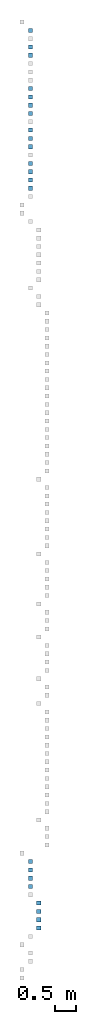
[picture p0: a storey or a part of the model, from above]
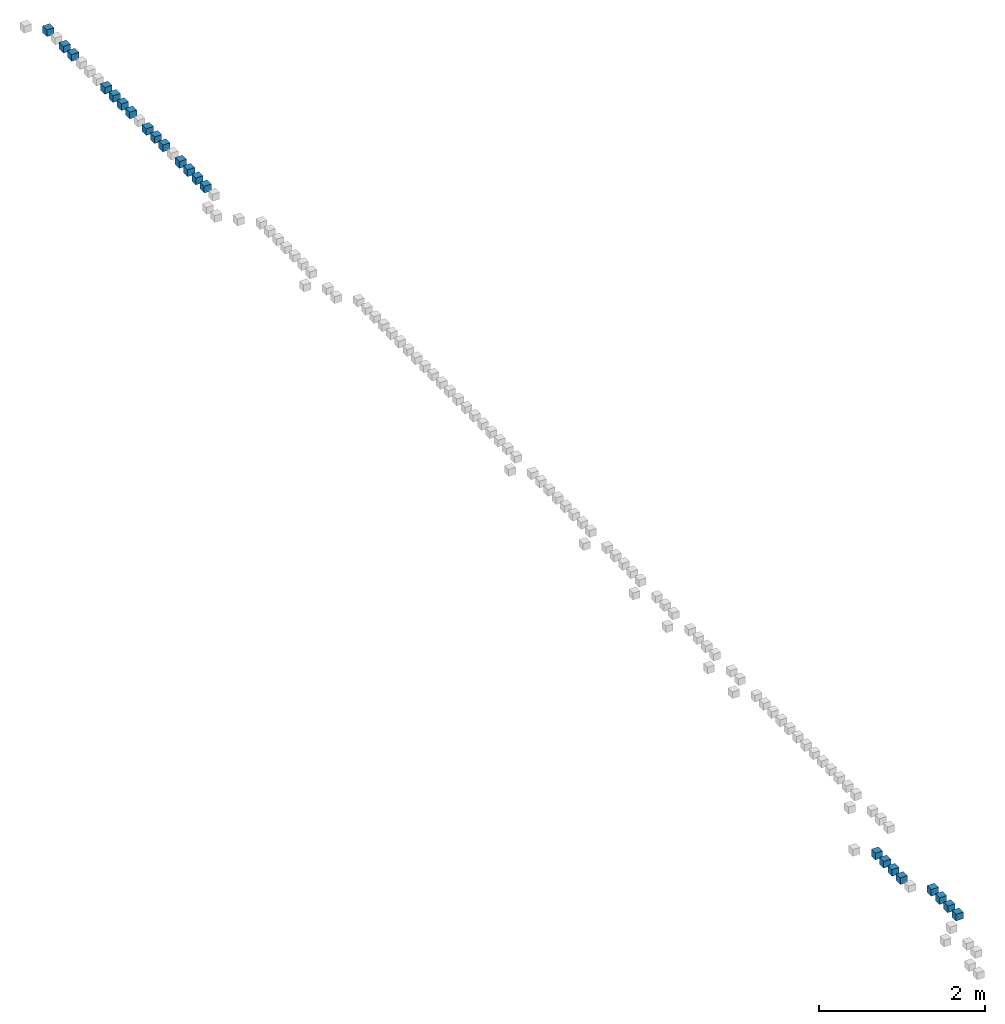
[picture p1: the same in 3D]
Properties of the parts of a building model (IFC4)

# File
Description: ViewDefinition [DesignTransferView_V1.0]
File name: 0001
Time: 2021-10-22T16:53:55
Written by: The EXPRESS Data Manager Version 5.02.0100.07 : 28 Aug 2013
Made in: 22.0.2.392 - Exporter 22.0.2.392 - Alternate UI 22.0.2.392

# IfcProject, 0001
LongName: Project Name; Phase: Project Status

# IfcSite, Default
RefLatitude: 42, 21, 31, 181945; RefLongitude: -71, -3, -24, -263305; RefElevation: 0 mm

# IfcSite: Generic Ifc Family:Generic Ifc Family, Generic Ifc Family:Generic Ifc Family:350329
Material: <Unnamed>

# IfcBuildingStorey: Level:8mm Head, Level 1
LongName: Level 1; Elevation: 0 mm

# IfcSpace: Generic Ifc Family:Generic Ifc Family, Generic Ifc Family:Generic Ifc Family:350332
Type - Material: <Unnamed>

# IfcActuator: Generic Ifc Family:Generic Ifc Family, Generic Ifc Family:Generic Ifc Family:349744
In: Level 1
Type - Material: <Unnamed>

# IfcAirTerminal: Generic Ifc Family:Generic Ifc Family, Generic Ifc Family:Generic Ifc Family:350142
In: Level 1
Type - Material: <Unnamed>

# IfcAirTerminalBox: Generic Ifc Family:Generic Ifc Family, Generic Ifc Family:Generic Ifc Family:349960
In: Level 1
Type - Material: <Unnamed>

# IfcAirToAirHeatRecovery: Generic Ifc Family:Generic Ifc Family, Generic Ifc Family:Generic Ifc Family:349855
In: Level 1
Type - Material: <Unnamed>

# IfcAlarm: Generic Ifc Family:Generic Ifc Family, Generic Ifc Family:Generic Ifc Family:349777
In: Level 1
Type - Material: <Unnamed>

# IfcAudioVisualAppliance: Generic Ifc Family:Generic Ifc Family, Generic Ifc Family:Generic Ifc Family:350154
In: Level 1
Type - Material: <Unnamed>

# IfcBeam: Generic Ifc Family:Generic Ifc Family, Generic Ifc Family:Generic Ifc Family:349537
In: Level 1
Type - PredefinedType: BEAM; Material: <Unnamed>

# IfcBoiler: Generic Ifc Family:Generic Ifc Family, Generic Ifc Family:Generic Ifc Family:349875
In: Level 1
Type - Material: <Unnamed>

# IfcBuildingElementPart: Generic Ifc Family:Generic Ifc Family, Generic Ifc Family:Generic Ifc Family:350225
In: Level 1
Type - Material: <Unnamed>

# IfcBuildingElementProxy: Generic Ifc Family:Generic Ifc Family (4)
In: Level 1
Type - Material: <Unnamed>
Name (Generic Ifc Family:Generic Ifc Family:...)
349545
349619
350213
350262

# IfcBurner: Generic Ifc Family:Generic Ifc Family, Generic Ifc Family:Generic Ifc Family:349888
In: Level 1
Type - Material: <Unnamed>

# IfcCableCarrierFitting: Generic Ifc Family:Generic Ifc Family, Generic Ifc Family:Generic Ifc Family:350023
In: Level 1
Type - Material: <Unnamed>

# IfcCableCarrierSegment: Generic Ifc Family:Generic Ifc Family, Generic Ifc Family:Generic Ifc Family:350096
In: Level 1
Type - Material: <Unnamed>

# IfcCableFitting: Generic Ifc Family:Generic Ifc Family, Generic Ifc Family:Generic Ifc Family:350039
In: Level 1
Type - Material: <Unnamed>

# IfcCableSegment: Generic Ifc Family:Generic Ifc Family, Generic Ifc Family:Generic Ifc Family:350097
In: Level 1
Type - Material: <Unnamed>

# IfcChiller: Generic Ifc Family:Generic Ifc Family, Generic Ifc Family:Generic Ifc Family:349891
In: Level 1
Type - Material: <Unnamed>

# IfcChimney: Generic Ifc Family:Generic Ifc Family, Generic Ifc Family:Generic Ifc Family:349558
In: Level 1
Type - Material: <Unnamed>

# IfcCivilElement: Generic Ifc Family:Generic Ifc Family, Generic Ifc Family:Generic Ifc Family:349694
In: Level 1
Type - Material: <Unnamed>

# IfcCoil: Generic Ifc Family:Generic Ifc Family, Generic Ifc Family:Generic Ifc Family:349894
In: Level 1
Type - Material: <Unnamed>

# IfcColumn: Generic Ifc Family:Generic Ifc Family, Generic Ifc Family:Generic Ifc Family:349561
In: Level 1
Type - PredefinedType: COLUMN; Material: <Unnamed>

# IfcCommunicationsAppliance: Generic Ifc Family:Generic Ifc Family, Generic Ifc Family:Generic Ifc Family:350167
In: Level 1
Type - Material: <Unnamed>

# IfcCompressor: Generic Ifc Family:Generic Ifc Family, Generic Ifc Family:Generic Ifc Family:350077
In: Level 1
Type - Material: <Unnamed>

# IfcCondenser: Generic Ifc Family:Generic Ifc Family, Generic Ifc Family:Generic Ifc Family:349897
In: Level 1
Type - Material: <Unnamed>

# IfcController: Generic Ifc Family:Generic Ifc Family, Generic Ifc Family:Generic Ifc Family:349790
In: Level 1
Type - Material: <Unnamed>

# IfcCooledBeam: Generic Ifc Family:Generic Ifc Family, Generic Ifc Family:Generic Ifc Family:349900
In: Level 1
Type - Material: <Unnamed>

# IfcCoolingTower: Generic Ifc Family:Generic Ifc Family, Generic Ifc Family:Generic Ifc Family:349903
In: Level 1
Type - Material: <Unnamed>

# IfcCurtainWall: Generic Ifc Family:Generic Ifc Family, Generic Ifc Family:Generic Ifc Family:349567
In: Level 1
Type - Material: <Unnamed>

# IfcDamper: Generic Ifc Family:Generic Ifc Family, Generic Ifc Family:Generic Ifc Family:349978
In: Level 1
Type - Material: <Unnamed>

# IfcDiscreteAccessory: Generic Ifc Family:Generic Ifc Family, Generic Ifc Family:Generic Ifc Family:350243
In: Level 1
Type - Material: <Unnamed>

# IfcDistributionChamberElement: Generic Ifc Family:Generic Ifc Family, Generic Ifc Family:Generic Ifc Family:349829
In: Level 1
Type - Material: <Unnamed>

# IfcDistributionControlElement: Generic Ifc Family:Generic Ifc Family, Generic Ifc Family:Generic Ifc Family:349720
In: Level 1
Type - Material: <Unnamed>

# IfcDistributionElement: Generic Ifc Family:Generic Ifc Family, Generic Ifc Family:Generic Ifc Family:349710
In: Level 1
Type - Material: <Unnamed>

# IfcDistributionFlowElement: Generic Ifc Family:Generic Ifc Family, Generic Ifc Family:Generic Ifc Family:349813
In: Level 1
Type - Material: <Unnamed>

# IfcDoor: Generic Ifc Family:Generic Ifc Family, Generic Ifc Family:Generic Ifc Family:349570
In: Level 1
Type - PredefinedType: DOOR; ParameterTakesPrecedence: no; Material: <Unnamed>
OverallHeight: 100 mm; OverallWidth: 100 mm

# IfcDuctFitting: Generic Ifc Family:Generic Ifc Family, Generic Ifc Family:Generic Ifc Family:350052
In: Level 1
Type - Material: <Unnamed>

# IfcDuctSegment: Generic Ifc Family:Generic Ifc Family, Generic Ifc Family:Generic Ifc Family:350098
In: Level 1
Type - Material: <Unnamed>

# IfcDuctSilencer: Generic Ifc Family:Generic Ifc Family, Generic Ifc Family:Generic Ifc Family:350201
In: Level 1
Type - Material: <Unnamed>

# IfcElectricAppliance: Generic Ifc Family:Generic Ifc Family, Generic Ifc Family:Generic Ifc Family:350170
In: Level 1
Type - Material: <Unnamed>

# IfcElectricDistributionBoard: Generic Ifc Family:Generic Ifc Family, Generic Ifc Family:Generic Ifc Family:349991
In: Level 1
Type - Material: <Unnamed>

# IfcElectricFlowStorageDevice: Generic Ifc Family:Generic Ifc Family, Generic Ifc Family:Generic Ifc Family:350119
In: Level 1
Type - Material: <Unnamed>

# IfcElectricGenerator: Generic Ifc Family:Generic Ifc Family, Generic Ifc Family:Generic Ifc Family:349906
In: Level 1
Type - Material: <Unnamed>

# IfcElectricMotor: Generic Ifc Family:Generic Ifc Family, Generic Ifc Family:Generic Ifc Family:349909
In: Level 1
Type - Material: <Unnamed>

# IfcElectricTimeControl: Generic Ifc Family:Generic Ifc Family, Generic Ifc Family:Generic Ifc Family:349994
In: Level 1
Type - Material: <Unnamed>

# IfcEnergyConversionDevice: Generic Ifc Family:Generic Ifc Family, Generic Ifc Family:Generic Ifc Family:349845
In: Level 1
Type - Material: <Unnamed>

# IfcEngine: Generic Ifc Family:Generic Ifc Family, Generic Ifc Family:Generic Ifc Family:349912
In: Level 1
Type - Material: <Unnamed>

# IfcEvaporativeCooler: Generic Ifc Family:Generic Ifc Family, Generic Ifc Family:Generic Ifc Family:349915
In: Level 1
Type - Material: <Unnamed>

# IfcEvaporator: Generic Ifc Family:Generic Ifc Family, Generic Ifc Family:Generic Ifc Family:349918
In: Level 1
Type - Material: <Unnamed>

# IfcFan: Generic Ifc Family:Generic Ifc Family, Generic Ifc Family:Generic Ifc Family:350078
In: Level 1
Type - Material: <Unnamed>

# IfcFastener: Generic Ifc Family:Generic Ifc Family, Generic Ifc Family:Generic Ifc Family:350256
In: Level 1
Type - Material: <Unnamed>

# IfcFilter: Generic Ifc Family:Generic Ifc Family, Generic Ifc Family:Generic Ifc Family:350202
In: Level 1
Type - Material: <Unnamed>

# IfcFireSuppressionTerminal: Generic Ifc Family:Generic Ifc Family, Generic Ifc Family:Generic Ifc Family:350173
In: Level 1
Type - Material: <Unnamed>

# IfcFlowController: Generic Ifc Family:Generic Ifc Family, Generic Ifc Family:Generic Ifc Family:349942
In: Level 1
Type - Material: <Unnamed>

# IfcFlowFitting: Generic Ifc Family:Generic Ifc Family, Generic Ifc Family:Generic Ifc Family:350009
In: Level 1
Type - Material: <Unnamed>

# IfcFlowInstrument: Generic Ifc Family:Generic Ifc Family, Generic Ifc Family:Generic Ifc Family:349793
In: Level 1
Type - Material: <Unnamed>

# IfcFlowMeter: Generic Ifc Family:Generic Ifc Family, Generic Ifc Family:Generic Ifc Family:349997
In: Level 1
Type - Material: <Unnamed>

# IfcFlowMovingDevice: Generic Ifc Family:Generic Ifc Family, Generic Ifc Family:Generic Ifc Family:350061
In: Level 1
Type - Material: <Unnamed>

# IfcFlowSegment: Generic Ifc Family:Generic Ifc Family, Generic Ifc Family:Generic Ifc Family:350095
In: Level 1
Type - Material: <Unnamed>

# IfcFlowStorageDevice: Generic Ifc Family:Generic Ifc Family, Generic Ifc Family:Generic Ifc Family:350118
In: Level 1
Type - Material: <Unnamed>

# IfcFlowTerminal: Generic Ifc Family:Generic Ifc Family, Generic Ifc Family:Generic Ifc Family:350141
In: Level 1
Type - Material: <Unnamed>

# IfcFlowTreatmentDevice: Generic Ifc Family:Generic Ifc Family, Generic Ifc Family:Generic Ifc Family:350200
In: Level 1
Type - Material: <Unnamed>

# IfcFooting: Generic Ifc Family:Generic Ifc Family, Generic Ifc Family:Generic Ifc Family:349573
In: Level 1
Type - Material: <Unnamed>

# IfcFurnishingElement: Generic Ifc Family:Generic Ifc Family, Generic Ifc Family:Generic Ifc Family:350292
In: Level 1
Type - Material: <Unnamed>

# IfcFurniture: Generic Ifc Family:Generic Ifc Family, Generic Ifc Family:Generic Ifc Family:350293
In: Level 1
Type - Material: <Unnamed>

# IfcGeographicElement: Generic Ifc Family:Generic Ifc Family, Generic Ifc Family:Generic Ifc Family:350304
In: Level 1
Type - Material: <Unnamed>

# IfcHeatExchanger: Generic Ifc Family:Generic Ifc Family, Generic Ifc Family:Generic Ifc Family:349921
In: Level 1
Type - Material: <Unnamed>

# IfcHumidifier: Generic Ifc Family:Generic Ifc Family, Generic Ifc Family:Generic Ifc Family:349924
In: Level 1
Type - Material: <Unnamed>

# IfcInterceptor: Generic Ifc Family:Generic Ifc Family, Generic Ifc Family:Generic Ifc Family:350203
In: Level 1
Type - Material: <Unnamed>

# IfcJunctionBox: Generic Ifc Family:Generic Ifc Family, Generic Ifc Family:Generic Ifc Family:350055
In: Level 1
Type - Material: <Unnamed>

# IfcLamp: Generic Ifc Family:Generic Ifc Family, Generic Ifc Family:Generic Ifc Family:350176
In: Level 1
Type - Material: <Unnamed>

# IfcLightFixture: Generic Ifc Family:Generic Ifc Family, Generic Ifc Family:Generic Ifc Family:350179
In: Level 1
Type - Material: <Unnamed>

# IfcMechanicalFastener: Generic Ifc Family:Generic Ifc Family, Generic Ifc Family:Generic Ifc Family:350259
In: Level 1
Type - Material: <Unnamed>

# IfcMedicalDevice: Generic Ifc Family:Generic Ifc Family, Generic Ifc Family:Generic Ifc Family:350182
In: Level 1
Type - Material: <Unnamed>

# IfcMember: Generic Ifc Family:Generic Ifc Family, Generic Ifc Family:Generic Ifc Family:349576
In: Level 1
Type - PredefinedType: BRACE; Material: <Unnamed>

# IfcMotorConnection: Generic Ifc Family:Generic Ifc Family, Generic Ifc Family:Generic Ifc Family:349927
In: Level 1
Type - Material: <Unnamed>

# IfcOutlet: Generic Ifc Family:Generic Ifc Family, Generic Ifc Family:Generic Ifc Family:350185
In: Level 1
Type - Material: <Unnamed>

# IfcPile: Generic Ifc Family:Generic Ifc Family, Generic Ifc Family:Generic Ifc Family:349579
In: Level 1
Type - Material: <Unnamed>

# IfcPipeFitting: Generic Ifc Family:Generic Ifc Family, Generic Ifc Family:Generic Ifc Family:350058
In: Level 1
Type - Material: <Unnamed>

# IfcPipeSegment: Generic Ifc Family:Generic Ifc Family, Generic Ifc Family:Generic Ifc Family:350108
In: Level 1
Type - Material: <Unnamed>

# IfcPlate: Generic Ifc Family:Generic Ifc Family, Generic Ifc Family:Generic Ifc Family:349582
In: Level 1
Type - Material: <Unnamed>

# IfcProtectiveDevice: Generic Ifc Family:Generic Ifc Family, Generic Ifc Family:Generic Ifc Family:350000
In: Level 1
Type - Material: <Unnamed>

# IfcProtectiveDeviceTrippingUnit: Generic Ifc Family:Generic Ifc Family, Generic Ifc Family:Generic Ifc Family:349796
In: Level 1
Type - Material: <Unnamed>

# IfcPump: Generic Ifc Family:Generic Ifc Family, Generic Ifc Family:Generic Ifc Family:350079
In: Level 1
Type - Material: <Unnamed>

# IfcRailing: Generic Ifc Family:Generic Ifc Family, Generic Ifc Family:Generic Ifc Family:349585
In: Level 1
Type - Material: <Unnamed>

# IfcRamp: Generic Ifc Family:Generic Ifc Family, Generic Ifc Family:Generic Ifc Family:349588
In: Level 1
Material: <Unnamed>

# IfcRampFlight: Generic Ifc Family:Generic Ifc Family, Generic Ifc Family:Generic Ifc Family:349591
In: Level 1
Type - Material: <Unnamed>

# IfcReinforcingBar: Generic Ifc Family:Generic Ifc Family, Generic Ifc Family:Generic Ifc Family:350265
In: Level 1
Type - Material: <Unnamed>

# IfcReinforcingMesh: Generic Ifc Family:Generic Ifc Family, Generic Ifc Family:Generic Ifc Family:350266
In: Level 1
Type - Material: <Unnamed>

# IfcRoof: Generic Ifc Family:Generic Ifc Family, Generic Ifc Family:Generic Ifc Family:349594
In: Level 1
Material: <Unnamed>

# IfcSanitaryTerminal: Generic Ifc Family:Generic Ifc Family, Generic Ifc Family:Generic Ifc Family:350188
In: Level 1
Type - Material: <Unnamed>

# IfcSensor: Generic Ifc Family:Generic Ifc Family, Generic Ifc Family:Generic Ifc Family:349799
In: Level 1
Type - Material: <Unnamed>

# IfcShadingDevice: Generic Ifc Family:Generic Ifc Family, Generic Ifc Family:Generic Ifc Family:349597
In: Level 1
Type - Material: <Unnamed>

# IfcSlab: Generic Ifc Family:Generic Ifc Family, Generic Ifc Family:Generic Ifc Family:349600
In: Level 1
Type - PredefinedType: FLOOR

# IfcSlab: Generic Ifc Family:Generic Ifc Family, Generic Ifc Family:Generic Ifc Family:349594:1
In: Level 1
Type - PredefinedType: ROOF

# IfcSolarDevice: Generic Ifc Family:Generic Ifc Family, Generic Ifc Family:Generic Ifc Family:349930
In: Level 1
Type - Material: <Unnamed>

# IfcSpaceHeater: Generic Ifc Family:Generic Ifc Family, Generic Ifc Family:Generic Ifc Family:350191
In: Level 1
Type - Material: <Unnamed>

# IfcStackTerminal: Generic Ifc Family:Generic Ifc Family, Generic Ifc Family:Generic Ifc Family:350194
In: Level 1
Type - Material: <Unnamed>

# IfcStair: Generic Ifc Family:Generic Ifc Family, Generic Ifc Family:Generic Ifc Family:349603
In: Level 1
Material: <Unnamed>

# IfcStairFlight: Generic Ifc Family:Generic Ifc Family, Generic Ifc Family:Generic Ifc Family:349606
In: Level 1
Type - Material: <Unnamed>

# IfcSwitchingDevice: Generic Ifc Family:Generic Ifc Family, Generic Ifc Family:Generic Ifc Family:350003
In: Level 1
Type - Material: <Unnamed>

# IfcSystemFurnitureElement: Generic Ifc Family:Generic Ifc Family, Generic Ifc Family:Generic Ifc Family:350294
In: Level 1
Type - Material: <Unnamed>

# IfcTank: Generic Ifc Family:Generic Ifc Family, Generic Ifc Family:Generic Ifc Family:350120
In: Level 1
Type - Material: <Unnamed>

# IfcTendon: Generic Ifc Family:Generic Ifc Family, Generic Ifc Family:Generic Ifc Family:350267
In: Level 1
Type - Material: <Unnamed>

# IfcTendonAnchor: Generic Ifc Family:Generic Ifc Family, Generic Ifc Family:Generic Ifc Family:350268
In: Level 1
Type - Material: <Unnamed>

# IfcTransformer: Generic Ifc Family:Generic Ifc Family, Generic Ifc Family:Generic Ifc Family:349933
In: Level 1
Type - Material: <Unnamed>

# IfcTransportElement: Generic Ifc Family:Generic Ifc Family, Generic Ifc Family:Generic Ifc Family:350316
In: Level 1
Type - Material: <Unnamed>

# IfcTubeBundle: Generic Ifc Family:Generic Ifc Family, Generic Ifc Family:Generic Ifc Family:349936
In: Level 1
Type - Material: <Unnamed>

# IfcUnitaryControlElement: Generic Ifc Family:Generic Ifc Family, Generic Ifc Family:Generic Ifc Family:349802
In: Level 1
Type - Material: <Unnamed>

# IfcUnitaryEquipment: Generic Ifc Family:Generic Ifc Family, Generic Ifc Family:Generic Ifc Family:349939
In: Level 1
Type - Material: <Unnamed>

# IfcValve: Generic Ifc Family:Generic Ifc Family, Generic Ifc Family:Generic Ifc Family:350006
In: Level 1
Type - Material: <Unnamed>

# IfcVibrationIsolator: Generic Ifc Family:Generic Ifc Family, Generic Ifc Family:Generic Ifc Family:350282
In: Level 1
Type - Material: <Unnamed>

# IfcWasteTerminal: Generic Ifc Family:Generic Ifc Family, Generic Ifc Family:Generic Ifc Family:350197
In: Level 1
Type - Material: <Unnamed>

# IfcWindow: Generic Ifc Family:Generic Ifc Family, Generic Ifc Family:Generic Ifc Family:349612
In: Level 1
Type - PredefinedType: WINDOW; ParameterTakesPrecedence: no; Material: <Unnamed>
OverallHeight: 100 mm; OverallWidth: 100 mm
